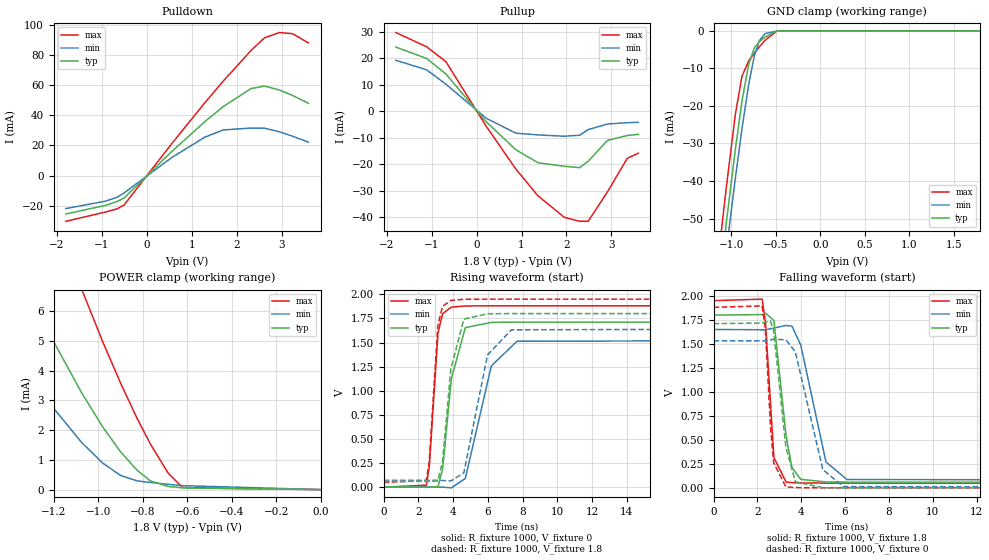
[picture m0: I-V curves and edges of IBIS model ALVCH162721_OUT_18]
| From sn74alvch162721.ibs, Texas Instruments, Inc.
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[Model]   ALVCH162721_OUT_18
Model_type  3-state
Enable   Active-Low
Vref =   0
Rref =   1000
Cref =   30p
Vmeas =   0.9
| variable   typ   min   max
C_comp   7.22pF   6.02pF   8.08pF
| C_pullup   6.36pF   4.54pF   8.44pF
| C_pulldown   4.93pF   4.26pF   5.67pF
| C_tri-state   7.22pF   6.02pF   8.08pF
[Temperature Range]   40   100   -40
| Ambient temperature   25   85   -40
[Voltage range]   1.8   1.65   1.95
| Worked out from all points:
|   slope of the pulldown table from 0 to 0.27 V, typ, clamps not added: 34.4 ohm
|   slope of the pullup table from 0 to 0.27 V, typ, clamps not added: 53.5 ohm
|   GND clamp passes 1 mA (typ) near -0.58 V on its own axis
|   POWER clamp passes 1 mA (typ) near -0.87 V on its own axis
|   rising waveform, R_fixture 1000, V_fixture 0: 20-80 % time 602ps typ, 1.14ns min, 381ps max; typ from 0 V to 1.71 V
|   falling waveform, R_fixture 1000, V_fixture 1.8: 20-80 % time 461ps typ, 819ps min, 284ps max; typ from 1.8 V to 0.059 V
|   rising waveform, R_fixture 1000, V_fixture 1.8: 20-80 % time 570ps typ, 1.01ns min, 371ps max; typ from 0.059 V to 1.8 V
|   falling waveform, R_fixture 1000, V_fixture 0: 20-80 % time 452ps typ, 823ps min, 280ps max; typ from 1.71 V to 0 V
[GND Clamp]
| ALVCH162721_OUT_18
|   Voltage   I(typ)   I(min)   I(max)
-1.8V     -210mA     -213mA     -207.4mA
-1.145V   -69.08mA   -76.12mA   -60.33mA
-1.105V   -60.91mA   -68.15mA   -51.83mA
-1.06V    -51.85mA   -59.31mA   -42.47mA
-955mV    -31.66mA   -39.37mA   -22.33mA
-880mV    -18.76mA   -26.09mA   -12.09mA
-805mV    -8.87mA    -14.33mA   -8.011mA
-740mV    -4.51mA    -6.526mA   -5.92mA
-685mV    -2.919mA   -2.619mA   -4.287mA
-620mV    -1.678mA   -732uA     -2.507mA
-485mV    -23.61uA   -60.57uA   -22.03uA
1.8V      60.47pA    9.416nA    28.01pA
[POWER Clamp]
| ALVCH162721_OUT_18
|   Voltage   I(typ)   I(min)   I(max)
-1.8V     15mA       10.16mA    22.87mA
-1.545V   10.46mA    6.724mA    16.81mA
-1.32V    6.769mA    4.004mA    11.77mA
-1.195V   4.893mA    2.678mA    9.129mA
-1.075V   3.254mA    1.585mA    6.738mA
-980mV    2.105mA    891.4uA    4.968mA
-900mV    1.273mA    476.4uA    3.581mA
-825mV    645.6uA    292.9uA    2.387mA
-765mV    290.1uA    239.7uA    1.523mA
-685mV    104.9uA    178.3uA    548.2uA
-620mV    56.95uA    132.3uA    61.78uA
-16.28fV  60.47pA    281.6pA    33.61pA
[Pulldown]
| ALVCH162721_OUT_18
|   Voltage   I(typ)   I(min)   I(max)
-1.8V     -25.44mA   -21.82mA   -30.27mA
-920mV    -19.72mA   -16.9mA    -24.14mA
-655mV    -17.11mA   -14.23mA   -21.96mA
-505mV    -14.79mA   -11.45mA   -19.4mA
555mV     15.94mA    11.96mA    21.16mA
1.295V    35.84mA    25.55mA    48.36mA
1.705V    45.8mA     30.27mA    62.74mA
2.32V     57.68mA    31.54mA    82.88mA
2.62V     59.41mA    31.45mA    91.32mA
2.955V    56.74mA    29.06mA    94.82mA
3.245V    53.15mA    26.12mA    94.08mA
3.6V      47.92mA    22.21mA    87.94mA
[Pullup]
| ALVCH162721_OUT_18
|   Voltage   I(typ)   I(min)   I(max)
-1.8V     24.15mA    19.17mA    29.63mA
-1.115V   19.87mA    15.59mA    24.29mA
-685mV    14.02mA    10.16mA    18.67mA
215mV     -4.052mA   -2.712mA   -5.747mA
875mV     -14.61mA   -8.332mA   -21.91mA
1.365V    -19.49mA   -8.984mA   -31.94mA
1.95V     -20.81mA   -9.486mA   -40.07mA
2.295V    -21.33mA   -9.102mA   -41.58mA
2.485V    -18.89mA   -6.966mA   -41.56mA
2.915V    -11.04mA   -4.874mA   -30.44mA
3.355V    -9.202mA   -4.369mA   -17.8mA
3.6V      -8.77mA    -4.222mA   -15.89mA
[Ramp]
| ALVCH162721_OUT_18
| variable   typ   min   max
dV/dt_r   1.03/6.10E-10   0.93/1.15E-09   1.13/3.91E-10
dV/dt_f   1.07/4.77E-10   0.98/8.48E-10   1.15/2.95E-10
R_load = 1000
[Rising Waveform]
| ALVCH162721_OUT_18
R_fixture =   1000
C_fixture =   0
L_fixture =   0
V_fixture =   0
V_fixture_min = 0
V_fixture_max = 0
|   Time   V(typ)   V(min)   V(max)
0s        309.1pV    1.643nV    216.2pV
2.46ns    826.8uV    632.7uV    20.52mV
2.63ns    -91.53uV   857.7uV    215.3mV
3.13ns    4.594mV    951.2uV    1.598V
3.4ns     191.7mV    -346.2uV   1.801V
3.9ns     1.125V     -7.445mV   1.867V
4.705ns   1.655V     90.06mV    1.879V
6.205ns   1.709V     1.258V     1.881V
7.685ns   1.711V     1.513V     1.881V
50ns      1.711V     1.532V     1.881V
[Falling Waveform]
| ALVCH162721_OUT_18
R_fixture =   1000
C_fixture =   0
L_fixture =   0
V_fixture =   1.8
V_fixture_min = 1.65
V_fixture_max = 1.95
|   Time   V(typ)   V(min)   V(max)
0s        1.8V       1.65V      1.95V
2.22ns    1.805V     1.647V     1.966V
2.37ns    1.82V      1.646V     1.723V
2.755ns   1.744V     1.665V     316.2mV
3.31ns    541.8mV    1.692V     60.34mV
3.58ns    210.4mV    1.684V     54.21mV
3.98ns    88.93mV    1.487V     51.32mV
5.13ns    61.37mV    269.9mV    49.48mV
6.085ns   59.89mV    86.96mV    49.31mV
50ns      59.49mV    70.7mV     49.27mV
[Rising Waveform]
| ALVCH162721_OUT_18
R_fixture =   1000
C_fixture =   0
L_fixture =   0
V_fixture =   1.8
V_fixture_min = 1.65
V_fixture_max = 1.95
|   Time   V(typ)   V(min)   V(max)
0s        59.49mV    70.7mV     49.27mV
2.455ns   59.89mV    71.16mV    69.18mV
2.625ns   58.88mV    71.21mV    265.9mV
3.12ns    64.72mV    70.69mV    1.674V
3.39ns    264.5mV    69.22mV    1.875V
3.87ns    1.225V     63.63mV    1.937V
4.62ns    1.743V     148.3mV    1.948V
5.985ns   1.798V     1.372V     1.95V
7.365ns   1.8V       1.632V     1.95V
50ns      1.8V       1.65V      1.95V
[Falling Waveform]
| ALVCH162721_OUT_18
R_fixture =   1000
C_fixture =   0
L_fixture =   0
V_fixture =   0
V_fixture_min = 0
V_fixture_max = 0
|   Time   V(typ)   V(min)   V(max)
0s        1.711V     1.532V     1.881V
2.215ns   1.716V     1.531V     1.895V
2.36ns    1.729V     1.531V     1.666V
2.605ns   1.735V     1.541V     621.3mV
2.745ns   1.635V     1.548V     260.1mV
3.3ns     427.2mV    1.542V     9.863mV
3.735ns   62.85mV    1.416V     2.923mV
4.985ns   1.721mV    191.5mV    214.7uV
5.915ns   322.8uV    13.37mV    36.6uV
50ns      -1.624nV   -4.356nV   -4.514nV
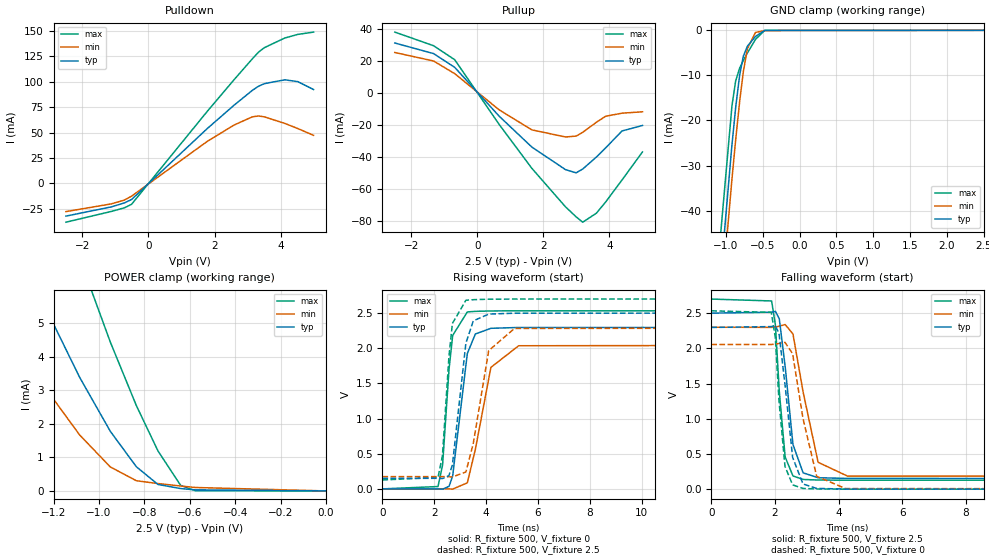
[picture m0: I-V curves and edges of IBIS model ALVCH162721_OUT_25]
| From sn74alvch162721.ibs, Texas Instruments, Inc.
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[Model]   ALVCH162721_OUT_25
Model_type  3-state
Enable   Active-Low
Vref =   0
Rref =   500
Cref =   30p
Vmeas =   1.25
| variable   typ   min   max
C_comp   6.94pF   5.73pF   7.97pF
| C_pullup   5.34pF   4.02pF   8.09pF
| C_pulldown   4.38pF   3.81pF   5.35pF
| C_tri-state   6.94pF   5.73pF   7.97pF
[Temperature Range]   40   100   -40
| Ambient temperature   25   85   -40
[Voltage range]   2.5   2.3   2.7
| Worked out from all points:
|   slope of the pulldown table from 0 to 0.375 V, typ, clamps not added: 32.2 ohm
|   slope of the pullup table from 0 to 0.375 V, typ, clamps not added: 44.5 ohm
|   GND clamp passes 1 mA (typ) near -0.58 V on its own axis
|   POWER clamp passes 1 mA (typ) near -0.87 V on its own axis
|   rising waveform, R_fixture 500, V_fixture 0: 20-80 % time 409ps typ, 588ps min, 294ps max; typ from 0 V to 2.3 V
|   falling waveform, R_fixture 500, V_fixture 2.5: 20-80 % time 307ps typ, 459ps min, 223ps max; typ from 2.5 V to 0.151 V
|   rising waveform, R_fixture 500, V_fixture 2.5: 20-80 % time 393ps typ, 541ps min, 288ps max; typ from 0.151 V to 2.5 V
|   falling waveform, R_fixture 500, V_fixture 0: 20-80 % time 305ps typ, 440ps min, 222ps max; typ from 2.3 V to 0 V
[GND Clamp]
| ALVCH162721_OUT_25
|   Voltage   I(typ)   I(min)   I(max)
-2.5V     -365.5mA   -364.2mA   -369.1mA
-1.15V    -70.11mA   -77.12mA   -61.4mA
-1.1V     -59.89mA   -67.17mA   -50.78mA
-1.07V    -53.85mA   -61.27mA   -44.53mA
-920mV    -25.41mA   -33.04mA   -16.8mA
-870mV    -17.21mA   -24.41mA   -11.25mA
-815mV    -9.914mA   -15.77mA   -8.372mA
-765mV    -5.726mA   -9.17mA    -6.695mA
-710mV    -3.527mA   -4.066mA   -5.017mA
-600mV    -1.345mA   -465.1uA   -2.004mA
-475mV    -16.47uA   -53.66uA   -12.1uA
2.5V      83.8pA     43.74nA    39.19pA
[POWER Clamp]
| ALVCH162721_OUT_25
|   Voltage   I(typ)   I(min)   I(max)
-2.5V     28.66mA    20.76mA    40.74mA
-1.575V   10.98mA    7.111mA    17.51mA
-1.55V    10.55mA    6.788mA    16.93mA
-1.33V    6.926mA    4.117mA    11.98mA
-1.205V   5.038mA    2.778mA    9.335mA
-1.085V   3.383mA    1.667mA    6.931mA
-950mV    1.776mA    714.5uA    4.435mA
-835mV    718.9uA    302.8uA    2.539mA
-740mV    193.1uA    219.7uA    1.192mA
-640mV    70.19uA    146.2uA    164.5uA
-575mV    31.48uA    102.2uA    6.344uA
-31.15fV  83.8pA     317.5pA    46.7pA
[Pulldown]
| ALVCH162721_OUT_25
|   Voltage   I(typ)   I(min)   I(max)
-2.5V     -32.15mA   -27.73mA   -38.12mA
-1.125V   -23.08mA   -20.13mA   -27.55mA
-730mV    -19.18mA   -16.4mA    -24.02mA
-510mV    -15.79mA   -12.5mA    -20.47mA
1.78V     53.88mA    41.29mA    70.78mA
2.595V    76.92mA    57.38mA    102mA
3.145V    91.41mA    65.4mA     122.4mA
3.335V    95.53mA    66.27mA    129.1mA
3.51V     98.04mA    65.4mA     133.4mA
4.13V     101.8mA    58.95mA    142.9mA
4.52V     100mA      53.93mA    146.4mA
5V        92.27mA    47.27mA    148.7mA
[Pullup]
| ALVCH162721_OUT_25
|   Voltage   I(typ)   I(min)   I(max)
-2.5V     31.01mA    25.1mA     37.8mA
-1.325V   24.4mA     19.8mA     29.3mA
-685mV    15.82mA    11.91mA    20.57mA
660mV     -14.56mA   -10.62mA   -19.69mA
1.65V     -33.8mA    -23.08mA   -47.03mA
2.67V     -47.85mA   -27.51mA   -71.03mA
2.99V     -49.83mA   -26.97mA   -77.22mA
3.19V     -47.48mA   -24.62mA   -80.57mA
3.605V    -40mA      -18.34mA   -74.96mA
3.885V    -34.3mA    -14.61mA   -67.99mA
4.38V     -23.77mA   -12.69mA   -54.3mA
5V        -20.35mA   -11.83mA   -36.82mA
[Ramp]
| ALVCH162721_OUT_25
| variable   typ   min   max
dV/dt_r   1.38/4.13E-10   1.24/5.97E-10   1.52/3.05E-10
dV/dt_f   1.43/3.16E-10   1.30/4.73E-10   1.55/2.34E-10
R_load = 500
[Rising Waveform]
| ALVCH162721_OUT_25
R_fixture =   500
C_fixture =   0
L_fixture =   0
V_fixture =   0
V_fixture_min = 0
V_fixture_max = 0
|   Time   V(typ)   V(min)   V(max)
0s        318.3pV    1.281nV    228.9pV
2.145ns   -151.6uV   837.9uV    33.26mV
2.32ns    -4.114mV   1.096mV    336.3mV
2.57ns    36.24mV    -71uV      1.704V
2.71ns    184.6mV    -2.832mV   2.182V
3.275ns   1.925V     85.67mV    2.517V
3.585ns   2.203V     561.6mV    2.525V
4.185ns   2.284V     1.728V     2.531V
5.255ns   2.296V     2.036V     2.533V
50ns      2.297V     2.055V     2.533V
[Falling Waveform]
| ALVCH162721_OUT_25
R_fixture =   500
C_fixture =   0
L_fixture =   0
V_fixture =   2.5
V_fixture_min = 2.3
V_fixture_max = 2.7
|   Time   V(typ)   V(min)   V(max)
0s        2.5V       2.3V       2.7V
1.895ns   2.513V     2.298V     2.673V
2.015ns   2.525V     2.302V     2.326V
2.135ns   2.42V      2.315V     1.391V
2.32ns    1.743V     2.338V     457.1mV
2.565ns   634.5mV    2.205V     187.8mV
2.885ns   231.4mV    1.378V     138.1mV
3.355ns   162.4mV    381.8mV    129.8mV
4.28ns    152.3mV    185.5mV    127.4mV
50ns      150.8mV    173.8mV    127mV
[Rising Waveform]
| ALVCH162721_OUT_25
R_fixture =   500
C_fixture =   0
L_fixture =   0
V_fixture =   2.5
V_fixture_min = 2.3
V_fixture_max = 2.7
|   Time   V(typ)   V(min)   V(max)
0s        150.8mV    173.8mV    127mV
2.145ns   150mV      174.3mV    162.6mV
2.315ns   146.3mV    174.2mV    468.9mV
2.565ns   188.1mV    172.6mV    1.878V
2.7ns     340.8mV    169.9mV    2.353V
3.22ns    2.074V     240.1mV    2.683V
3.505ns   2.39V      646.5mV    2.691V
4.1ns     2.486V     1.967V     2.698V
5.095ns   2.499V     2.282V     2.7V
50ns      2.5V       2.3V       2.7V
[Falling Waveform]
| ALVCH162721_OUT_25
R_fixture =   500
C_fixture =   0
L_fixture =   0
V_fixture =   0
V_fixture_min = 0
V_fixture_max = 0
|   Time   V(typ)   V(min)   V(max)
0s        2.297V     2.055V     2.533V
1.885ns   2.309V     2.055V     2.511V
2.01ns    2.319V     2.059V     2.156V
2.125ns   2.218V     2.069V     1.262V
2.315ns   1.486V     2.085V     321.8mV
2.555ns   450.8mV    1.923V     61.01mV
2.88ns    73.68mV    1.005V     10.22mV
3.31ns    10.92mV    182.4mV    2.578mV
4.22ns    1.269mV    8.686mV    361.9uV
50ns      -9.842nV   -5.463nV   -3.096nV
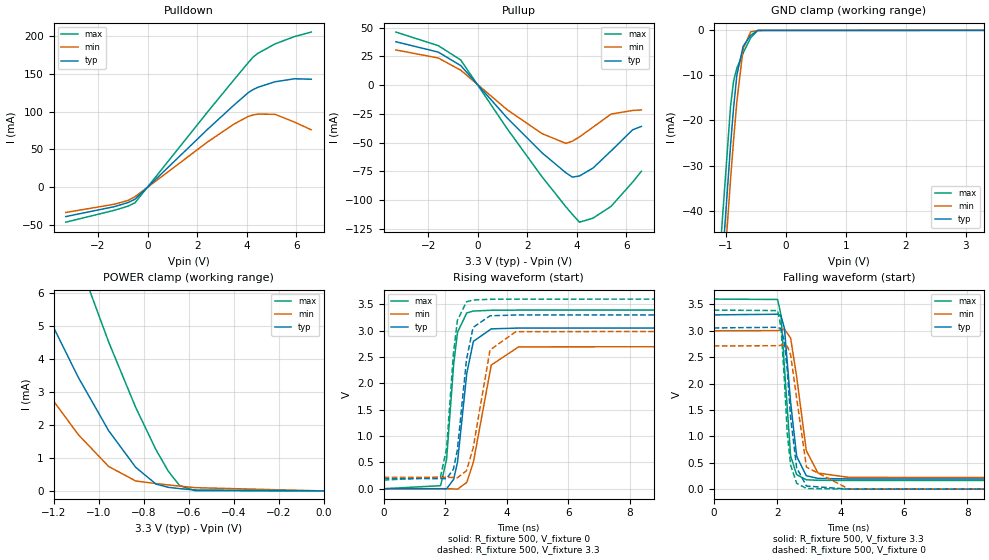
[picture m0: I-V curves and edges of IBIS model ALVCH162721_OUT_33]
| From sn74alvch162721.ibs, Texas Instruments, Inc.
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[Model]   ALVCH162721_OUT_33
Model_type  3-state
Enable   Active-Low
Vref =   0
Rref =   500
Cref =   50p
Vmeas =   1.5
| variable   typ   min   max
C_comp   6.69pF   5.51pF   7.90pF
| C_pullup   4.76pF   3.67pF   6.93pF
| C_pulldown   4.12pF   3.48pF   5.31pF
| C_tri-state   6.69pF   5.51pF   7.90pF
[Temperature Range]   40   100   -40
| Ambient temperature   25   85   -40
[Voltage range]   3.3   3   3.6
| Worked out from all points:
|   slope of the pulldown table from 0 to 0.495 V, typ, clamps not added: 31 ohm
|   slope of the pullup table from 0 to 0.495 V, typ, clamps not added: 40.8 ohm
|   GND clamp passes 1 mA (typ) near -0.58 V on its own axis
|   POWER clamp passes 1 mA (typ) near -0.87 V on its own axis
|   rising waveform, R_fixture 500, V_fixture 0: 20-80 % time 341ps typ, 469ps min, 271ps max; typ from 0 V to 3.05 V
|   falling waveform, R_fixture 500, V_fixture 3.3: 20-80 % time 257ps typ, 347ps min, 205ps max; typ from 3.3 V to 0.192 V
|   rising waveform, R_fixture 500, V_fixture 3.3: 20-80 % time 335ps typ, 449ps min, 268ps max; typ from 0.192 V to 3.3 V
|   falling waveform, R_fixture 500, V_fixture 0: 20-80 % time 259ps typ, 339ps min, 207ps max; typ from 3.05 V to 0 V
[GND Clamp]
| ALVCH162721_OUT_33
|   Voltage   I(typ)   I(min)   I(max)
-3.3V     -545.2mA   -539.1mA   -555.7mA
-1.16V    -72.17mA   -79.12mA   -63.55mA
-1.14V    -68.05mA   -75.12mA   -59.26mA
-1.1V     -59.89mA   -67.17mA   -50.78mA
-1.065V   -52.85mA   -60.29mA   -43.5mA
-920mV    -25.41mA   -33.04mA   -16.8mA
-870mV    -17.21mA   -24.41mA   -11.25mA
-815mV    -9.914mA   -15.77mA   -8.372mA
-710mV    -3.527mA   -4.066mA   -5.017mA
-585mV    -1.109mA   -319.5uA   -1.646mA
-465mV    -12.37uA   -47.37uA   -8.152uA
3.3V      114.4pA    941.2nA    51.31pA
[POWER Clamp]
| ALVCH162721_OUT_33
|   Voltage   I(typ)   I(min)   I(max)
-3.3V     45.5mA     34.01mA    62.51mA
-1.565V   10.81mA    6.981mA    17.27mA
-1.335V   7.004mA    4.173mA    12.09mA
-1.205V   5.038mA    2.778mA    9.335mA
-1.09V    3.449mA    1.71mA     7.028mA
-955mV    1.83mA     742.3uA    4.523mA
-835mV    718.9uA    302.8uA    2.539mA
-745mV    209.6uA    223.6uA    1.256mA
-690mV    109.3uA    182uA      600.5uA
-640mV    70.19uA    146.2uA    164.5uA
-570mV    29.05uA    98.95uA    5.202uA
-48.03fV  114.4pA    359.8pA    62.68pA
[Pulldown]
| ALVCH162721_OUT_33
|   Voltage   I(typ)   I(min)   I(max)
-3.3V     -39.34mA   -33.9mA    -46.82mA
-1.345V   -26.22mA   -23.01mA   -31.03mA
-795mV    -20.79mA   -17.99mA   -25.61mA
-510mV    -16.35mA   -13.06mA   -21.09mA
2.41V     76.27mA    59.51mA    99.29mA
3.47V     108.3mA    83.2mA     141.8mA
4.065V    125.4mA    93.8mA     165.3mA
4.25V     129.2mA    95.52mA    172.3mA
4.45V     132.4mA    96.76mA    177.5mA
5.14V     139.7mA    96.49mA    190mA
5.93V     143.7mA    86.07mA    199.8mA
6.6V      143.1mA    75.95mA    205.7mA
[Pullup]
| ALVCH162721_OUT_33
|   Voltage   I(typ)   I(min)   I(max)
-3.3V     37.7mA     30.59mA    46.11mA
-1.59V    28.69mA    23.58mA    34.31mA
-685mV    16.99mA    12.99mA    21.85mA
1.19V     -28.54mA   -21.41mA   -37.91mA
2.595V    -58.82mA   -42.14mA   -79.72mA
3.56V     -76.23mA   -50.65mA   -105.8mA
3.82V     -79.94mA   -48.68mA   -112.4mA
4.105V    -78.9mA    -44.95mA   -119.1mA
4.65V     -72.04mA   -36.55mA   -115.6mA
5.375V    -57.26mA   -25.15mA   -105.4mA
6.25V     -38.78mA   -22mA      -84.26mA
6.6V      -35.87mA   -21.53mA   -74.86mA
[Ramp]
| ALVCH162721_OUT_33
| variable   typ   min   max
dV/dt_r   1.83/3.49E-10   1.63/4.78E-10   2.04/2.77E-10
dV/dt_f   1.87/2.61E-10   1.69/3.56E-10   2.07/2.16E-10
R_load = 500
[Rising Waveform]
| ALVCH162721_OUT_33
R_fixture =   500
C_fixture =   0
L_fixture =   0
V_fixture =   0
V_fixture_min = 0
V_fixture_max = 0
|   Time   V(typ)   V(min)   V(max)
0s        397.6pV    1.172nV    255.3pV
1.85ns    -1.201mV   905.3uV    57.76mV
2.045ns   -2.376mV   599.4uV    560.2mV
2.275ns   180.6mV    -3.686mV   2.368V
2.4ns     507.4mV    -8.243mV   2.97V
2.7ns     2.188V     119.3mV    3.337V
2.915ns   2.797V     503.9mV    3.373V
3.495ns   3.034V     2.347V     3.387V
4.385ns   3.05V      2.693V     3.391V
50ns      3.053V     2.712V     3.391V
[Falling Waveform]
| ALVCH162721_OUT_33
R_fixture =   500
C_fixture =   0
L_fixture =   0
V_fixture =   3.3
V_fixture_min = 3
V_fixture_max = 3.6
|   Time   V(typ)   V(min)   V(max)
0s        3.3V       3V         3.6V
2.015ns   3.313V     3.003V     3.592V
2.12ns    3.287V     3.014V     3.297V
2.23ns    3.045V     3.029V     2.303V
2.425ns   1.644V     2.863V     626mV
2.615ns   623.1mV    2.13V      275.5mV
2.92ns    254.1mV    728.8mV    177.8mV
3.29ns    203.8mV    305.1mV    168.3mV
4.265ns   193.6mV    222.6mV    165mV
50ns      192.3mV    217.1mV    164.5mV
[Rising Waveform]
| ALVCH162721_OUT_33
R_fixture =   500
C_fixture =   0
L_fixture =   0
V_fixture =   3.3
V_fixture_min = 3
V_fixture_max = 3.6
|   Time   V(typ)   V(min)   V(max)
0s        192.3mV    217.1mV    164.5mV
1.845ns   190.8mV    217.6mV    219.3mV
2.045ns   190.1mV    217mV      764.3mV
2.265ns   369.8mV    212.8mV    2.553V
2.395ns   736.6mV    208.5mV    3.193V
2.69ns    2.448V     340.5mV    3.548V
2.905ns   3.062V     765.9mV    3.582V
3.455ns   3.282V     2.634V     3.596V
4.295ns   3.298V     2.982V     3.599V
50ns      3.3V       3V         3.6V
[Falling Waveform]
| ALVCH162721_OUT_33
R_fixture =   500
C_fixture =   0
L_fixture =   0
V_fixture =   0
V_fixture_min = 0
V_fixture_max = 0
|   Time   V(typ)   V(min)   V(max)
0s        3.053V     2.712V     3.391V
2.015ns   3.066V     2.716V     3.382V
2.12ns    3.036V     2.725V     3.077V
2.225ns   2.799V     2.739V     2.106V
2.32ns    2.246V     2.705V     1.053V
2.425ns   1.353V     2.547V     452.5mV
2.615ns   406mV      1.724V     112mV
2.925ns   59.49mV    417.7mV    12.97mV
4.26ns    1.081mV    4.112mV    415.1uV
50ns      -18.8nV    -454.8pV   -3.405nV
